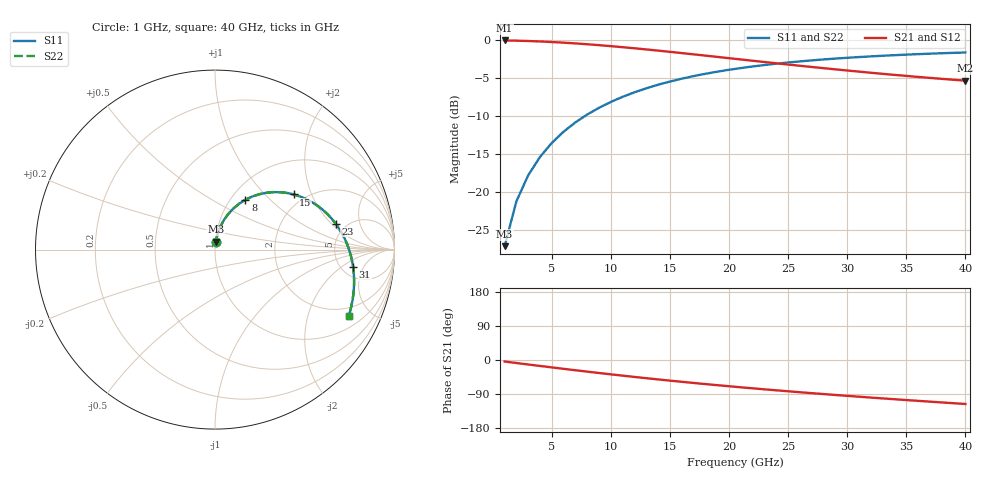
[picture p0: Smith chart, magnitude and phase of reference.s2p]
! circuitRF F0 spike reference -- case A, Palace, perimeter-matched hexagon, no foot
! Palace postpro/port-S.csv, dB/deg -> RI; port 1 excited only; S22 = S11 and S12 = S21 by the mirror symmetry of the geometry about x = 0
# GHz S RI R 50
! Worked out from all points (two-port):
!   40 points, 1 GHz to 40 GHz, reference 50 ohm
!   highest |S21| = -0.02 dB at 1 GHz (marker M1); lowest = -5.3 dB at 40 GHz (marker M2)
!   |S21| within 3 dB of the highest: start of sweep to 23.97 GHz
!   lowest |S11| = -27.1 dB at 1 GHz (marker M3), VSWR 1.09, Z = 50.3 + j4.42 ohm
!   |S11| at or under -10 dB: start of sweep to 7.771 GHz
!   |S22| runs from -27.1 to -1.6 dB; largest |S21 - S12| = 0
!   S11 on the Smith chart (normalised r, x): 1 GHz: 1.01, +0.09; 8 GHz: 1.17, +0.72; 15 GHz: 1.74, +1.50; 23 GHz: 4.10, +2.26; 31 GHz: 6.36, -3.12; 40 GHz: 1.53, -3.66
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1  0.00445 0.0439  0.9952 -0.0695  0.9952 -0.0695  0.00445 0.0439
2  0.014 0.086  0.9847 -0.1373  0.9847 -0.1373  0.014 0.086
3  0.0289 0.1262  0.9681 -0.203  0.9681 -0.203  0.0289 0.1262
4  0.0489 0.1637  0.9458 -0.2661  0.9458 -0.2661  0.0489 0.1637
5  0.0736 0.1981  0.9182 -0.3259  0.9182 -0.3259  0.0736 0.1981
6  0.1023 0.2288  0.8858 -0.382  0.8858 -0.382  0.1023 0.2288
7  0.1344 0.2553  0.8495 -0.4338  0.8495 -0.4338  0.1344 0.2553
8  0.1692 0.2774  0.8097 -0.4811  0.8097 -0.4811  0.1692 0.2774
9  0.2061 0.295  0.7671 -0.5237  0.7671 -0.5237  0.2061 0.295
11  0.2837 0.3164  0.6765 -0.5947  0.6765 -0.5947  0.2837 0.3164
12  0.3231 0.3203  0.6295 -0.6232  0.6295 -0.6232  0.3231 0.3203
14  0.4007 0.3156  0.5349 -0.6671  0.5349 -0.6671  0.4007 0.3156
15  0.4381 0.3076  0.4881 -0.683  0.4881 -0.683  0.4381 0.3076
18  0.541 0.2641  0.3532 -0.7098  0.3532 -0.7098  0.541 0.2641
21  0.6262 0.198  0.2305 -0.7114  0.2305 -0.7114  0.6262 0.198
23  0.672 0.1453  0.1568 -0.7022  0.1568 -0.7022  0.672 0.1453
25  0.7089 0.0878  0.0897 -0.6868  0.0897 -0.6868  0.7089 0.0878
27  0.7372 0.0274  0.029 -0.6668  0.029 -0.6668  0.7372 0.0274
31  0.7696 -0.0978  -0.0746 -0.6174  -0.0746 -0.6174  0.7696 -0.0978
34  0.7749 -0.1916  -0.1387 -0.5756  -0.1387 -0.5756  0.7749 -0.1916
37  0.7661 -0.2827  -0.1927 -0.5318  -0.1927 -0.5318  0.7661 -0.2827
40  0.7448 -0.3697  -0.2382 -0.4872  -0.2382 -0.4872  0.7448 -0.3697
